VERSION 5.8 ;
BUSBITCHARS "[]" ;
DIVIDERCHAR "/" ;

UNITS
  DATABASE MICRONS 1000 ;
END UNITS

MANUFACTURINGGRID 0.001 ;

PROPERTYDEFINITIONS
  LAYER LEF58_VOLTAGESPACING STRING ;
END PROPERTYDEFINITIONS

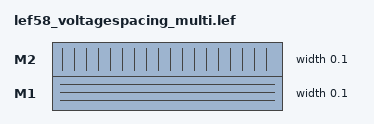
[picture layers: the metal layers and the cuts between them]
LAYER M1
  TYPE ROUTING ;
  DIRECTION HORIZONTAL ;
  WIDTH 0.1 ;
  PROPERTY LEF58_VOLTAGESPACING "
    VOLTAGESPACING
    1.2     0.075
    3.3     0.150 ;
    VOLTAGESPACING TOCUT ABOVE
    1.2     0.080
    5.0     0.300 ; " ;
END M1

LAYER M2
  TYPE ROUTING ;
  DIRECTION VERTICAL ;
  WIDTH 0.1 ;
  PROPERTY LEF58_VOLTAGESPACING "
    VOLTAGESPACING
    1.2     0.075 ;
    VOLTAGESPACING TOCUT
    1.2 ; " ;
END M2

END LIBRARY
